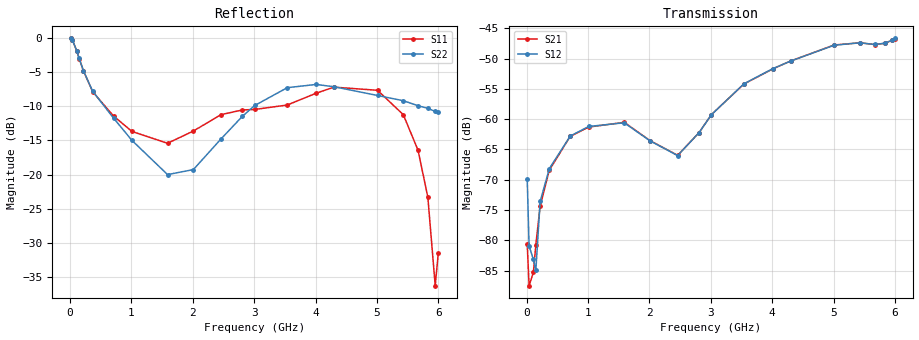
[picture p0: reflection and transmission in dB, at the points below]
!Agilent Technologies,N5230A,MY45001650,A.07.50.48
!Agilent N5230A: A.07.50.48
!Date: Saturday, July 08, 2017 16:00:09
!Correction: S11(Full 2 Port(1,2))
!S21(Full 2 Port(1,2))
!S12(Full 2 Port(1,2))
!S22(Full 2 Port(1,2))
!S2P File: Measurements: S11, S21, S12, S22:
# Hz S  dB  R 50
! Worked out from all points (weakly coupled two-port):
!   600 points, 10 MHz to 6 GHz, reference 50 ohm
!   highest |S21| = -46.73 dB at 6 GHz (marker M1); lowest = -87.5 dB at 40 MHz (marker M2)
!   lowest |S11| = -36.2 dB at 5.95 GHz (marker M3), VSWR 1.03, Z = 48.6 - j0.526 ohm
!   |S11| at or under -10 dB: 544.6 MHz to 3.502 GHz (2.957 GHz wide, 146 % of centre); 5.33 GHz to end of sweep
!   |S22| runs from -20.7 to -0.1 dB; largest |S21 - S12| = 0.00029
!   S11 on the Smith chart (normalised r, x): 10 MHz: 2, -19; 110 MHz: 0.49, -1.80; 370 MHz: 0.53, -0.43; 2.81 GHz: 0.59, +0.25; 4.3 GHz: 2.42, +0.49; 6 GHz: 0.97, +0.04
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1e7  -0.11 -6.0  -80.66 -50.1  -69.94 12.1  -0.11 -5.7
4e7  -0.37 -22.5  -87.46 -95.9  -80.90 -25.8  -0.35 -21.5
1.1e8  -1.94 -55.4  -85.28 161.7  -83.14 119.5  -1.91 -52.8
1.5e8  -3.05 -70.1  -80.68 134.8  -84.94 120.1  -3.02 -66.6
2.2e8  -4.88 -90.6  -74.35 116.6  -73.57 117.7  -4.84 -85.9
3.7e8  -7.90 -121.7  -68.40 88.5  -68.15 89.9  -7.84 -113.4
7.1e8  -11.45 -164.6  -62.84 51.6  -62.79 52.0  -11.75 -148.4
1.01e9  -13.70 176.2  -61.31 22.6  -61.21 22.7  -15.01 -165.5
1.59e9  -15.43 168.6  -60.52 -27.6  -60.60 -27.6  -20.00 -179.6
2.01e9  -13.64 172.0  -63.53 -75.3  -63.58 -76.0  -19.27 -174.9
2.46e9  -11.25 157.5  -65.96 -165.5  -66.01 -165.2  -14.80 172.5
2.81e9  -10.56 140.0  -62.21 123.6  -62.21 123.7  -11.48 160.9
3.01e9  -10.49 124.0  -59.25 95.2  -59.27 95.4  -9.91 152.7
3.54e9  -9.84 73.9  -54.21 48.8  -54.17 49.0  -7.31 135.7
4.01e9  -8.12 29.6  -51.72 8.0  -51.67 8.2  -6.84 119.0
4.3e9  -7.23 10.9  -50.41 -10.7  -50.43 -10.5  -7.17 107.8
5.01e9  -7.69 -22.6  -47.77 -62.2  -47.81 -62.2  -8.45 69.8
5.43e9  -11.25 -42.7  -47.41 -95.7  -47.41 -95.6  -9.21 43.1
5.67e9  -16.44 -55.7  -47.70 -112.8  -47.69 -112.6  -9.94 28.3
5.83e9  -23.30 -69.5  -47.51 -119.1  -47.48 -119.1  -10.33 18.2
5.95e9  -36.22 -159.5  -47.01 -125.3  -47.01 -125.2  -10.78 12.0
6e9  -31.49 123.3  -46.73 -128.6  -46.68 -128.2  -10.84 9.3
